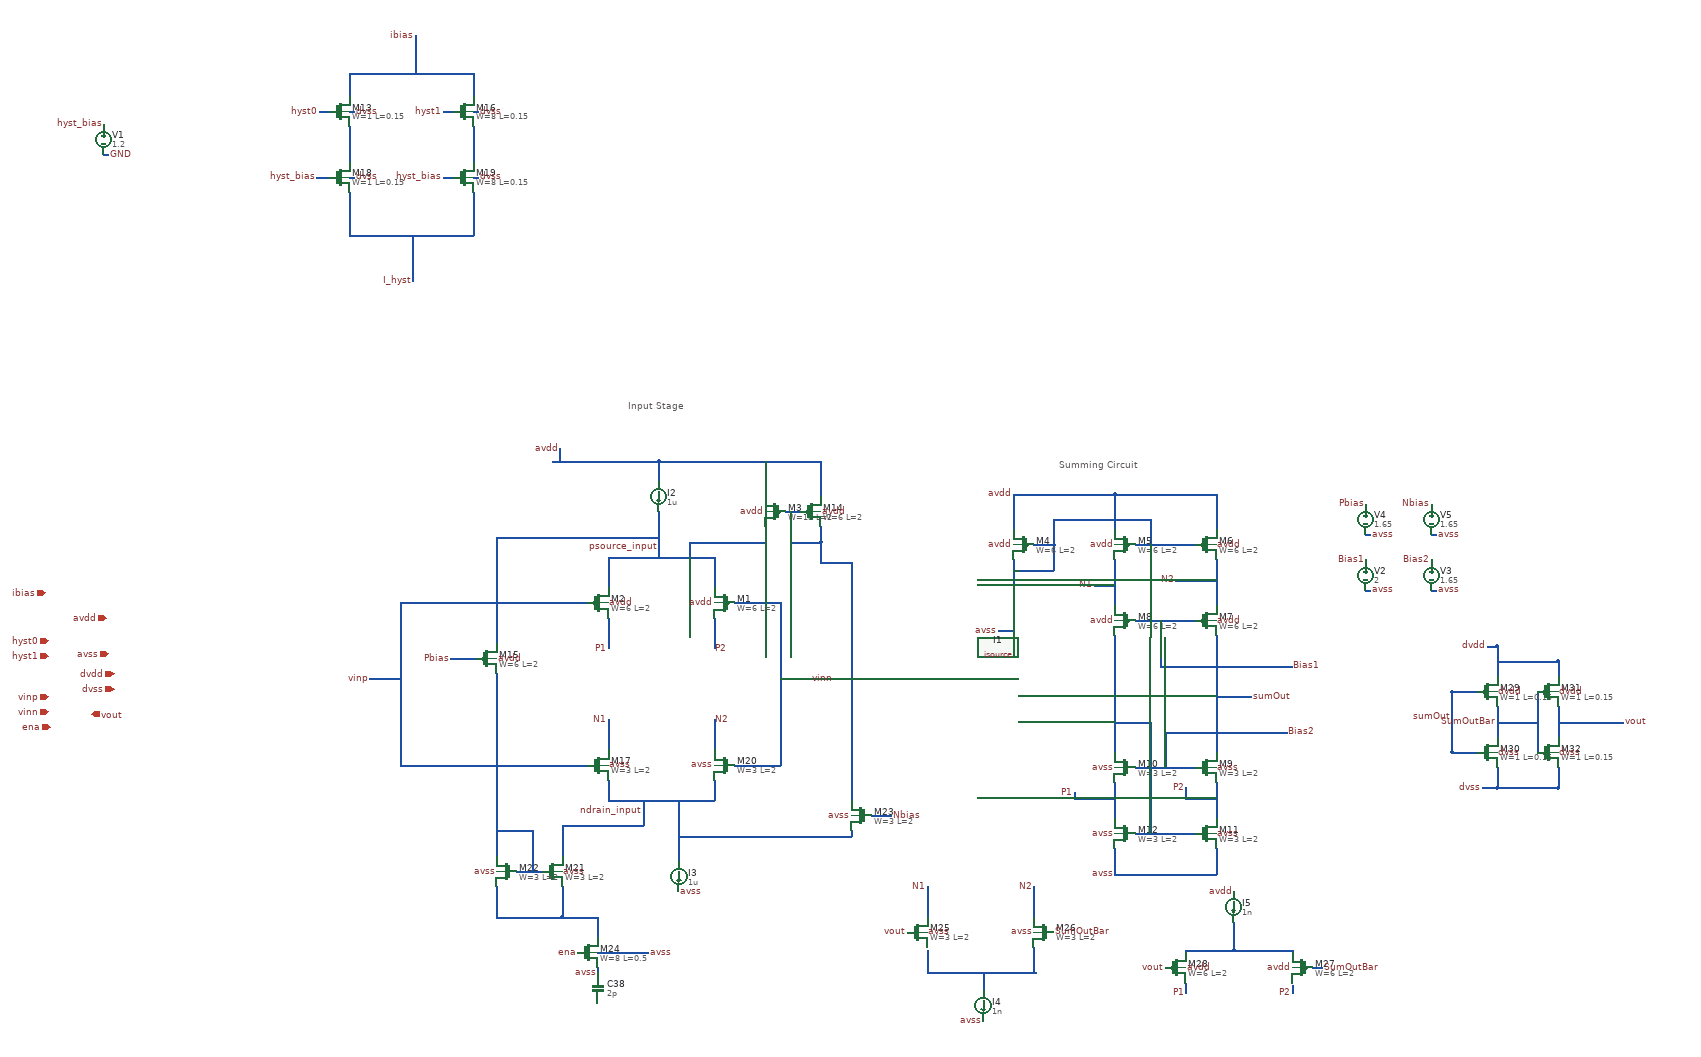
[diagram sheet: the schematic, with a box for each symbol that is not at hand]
v {xschem version=3.4.5 file_version=1.2
}
G {}
K {}
V {}
S {}
E {}
T {Summing Circuit} 2105 -1180 0 0 0.5 0.5 {}
T {Input Stage} 1255 -1295 0 0 0.5 0.5 {}
N 705 -1865 715 -1865 {
lab=dvss}
N 830 -1550 830 -1530 {
lab=I_hyst}
N 830 -1570 830 -1550 {
lab=I_hyst}
N 830 -1620 830 -1570 {
lab=I_hyst}
N 950 -1865 960 -1865 {
lab=dvss}
N 890 -1865 910 -1865 {
lab=hyst1}
N 950 -1835 950 -1765 {
lab=#net1}
N 950 -1735 960 -1735 {
lab=dvss}
N 705 -1835 705 -1765 {
lab=#net2}
N 705 -1835 705 -1765 {
lab=#net2}
N 950 -1705 950 -1675 {
lab=I_hyst}
N 705 -1685 705 -1620 {
lab=I_hyst}
N 705 -1705 705 -1685 {
lab=I_hyst}
N 950 -1675 950 -1620 {
lab=I_hyst}
N 705 -1735 715 -1735 {
lab=dvss}
N 950 -1940 950 -1895 {
lab=ibias}
N 705 -1940 705 -1895 {
lab=ibias}
N 705 -1620 950 -1620 {
lab=I_hyst}
N 705 -1940 950 -1940 {
lab=ibias}
N 835 -2015 835 -1940 {
lab=ibias}
N 890 -1735 910 -1735 {
lab=hyst_bias}
N 640 -1735 665 -1735 {
lab=hyst_bias}
N 645 -1865 665 -1865 {
lab=hyst0}
N 220 -1780 230 -1780 {
lab=GND}
N 2970 -690 2970 -630 {
lab=SumOutBar}
N 2880 -720 2930 -720 {
lab=sumOut}
N 2880 -600 2930 -600 {
lab=sumOut}
N 2880 -720 2880 -600 {
lab=sumOut}
N 3090 -660 3220 -660 {
lab=vout}
N 2970 -810 2970 -750 {
lab=dvdd}
N 2950 -810 2970 -810 {
lab=dvdd}
N 2970 -570 2970 -530 {
lab=dvss}
N 2940 -530 2970 -530 {
lab=dvss}
N 2710 -920 2720 -920 {
lab=avss}
N 2840 -920 2850 -920 {
lab=avss}
N 2710 -1030 2720 -1030 {
lab=avss}
N 2840 -1030 2850 -1030 {
lab=avss}
N 3090 -690 3090 -630 {
lab=vout}
N 3050 -720 3050 -600 {
lab=SumOutBar}
N 3090 -780 3090 -750 {
lab=dvdd}
N 2970 -780 3090 -780 {
lab=dvdd}
N 3090 -570 3090 -530 {
lab=dvss}
N 2970 -530 3090 -530 {
lab=dvss}
N 2970 -690 2970 -630 {
lab=SumOutBar}
N 2880 -720 2930 -720 {
lab=sumOut}
N 2880 -600 2930 -600 {
lab=sumOut}
N 2880 -720 2880 -600 {
lab=sumOut}
N 3090 -660 3220 -660 {
lab=vout}
N 2970 -810 2970 -750 {
lab=dvdd}
N 2950 -810 2970 -810 {
lab=dvdd}
N 2970 -570 2970 -530 {
lab=dvss}
N 2940 -530 2970 -530 {
lab=dvss}
N 3090 -690 3090 -630 {
lab=vout}
N 3050 -720 3050 -600 {
lab=SumOutBar}
N 3090 -780 3090 -750 {
lab=dvdd}
N 2970 -780 3090 -780 {
lab=dvdd}
N 3090 -570 3090 -530 {
lab=dvss}
N 2970 -530 3090 -530 {
lab=dvss}
N 2970 -660 3050 -660 {
lab=SumOutBar}
N 2015 -980 2015 -930 {
lab=#net3}
N 2015 -960 2095 -960 {
lab=#net3}
N 2095 -1010 2095 -960 {
lab=#net3}
N 2055 -1010 2095 -1010 {
lab=#net3}
N 2015 -1110 2015 -1040 {
lab=avdd}
N 2015 -1110 2215 -1110 {
lab=avdd}
N 2215 -1110 2215 -1040 {
lab=avdd}
N 2215 -1110 2395 -1110 {
lab=avdd}
N 2415 -1110 2415 -1040 {
lab=avdd}
N 2395 -1110 2415 -1110 {
lab=avdd}
N 2255 -1010 2375 -1010 {
lab=#net3}
N 2285 -1060 2285 -1010 {
lab=#net3}
N 2095 -1060 2285 -1060 {
lab=#net3}
N 2095 -1060 2095 -1010 {
lab=#net3}
N 2215 -980 2215 -920 {
lab=N1}
N 2415 -980 2415 -890 {
lab=N2}
N 2335 -940 2415 -940 {
lab=N2}
N 2335 -860 2375 -860 {
lab=Bias1}
N 2255 -860 2335 -860 {
lab=Bias1}
N 2215 -920 2215 -890 {
lab=N1}
N 2415 -830 2415 -600 {
lab=sumOut}
N 2215 -830 2215 -600 {
lab=#net4}
N 2255 -570 2375 -570 {
lab=Bias2}
N 2415 -540 2415 -470 {
lab=P2}
N 2355 -510 2415 -510 {
lab=P2}
N 2355 -530 2355 -510 {
lab=P2}
N 2215 -540 2215 -470 {
lab=P1}
N 2255 -440 2375 -440 {
lab=#net4}
N 2215 -410 2215 -360 {
lab=avss}
N 2215 -360 2415 -360 {
lab=avss}
N 2415 -410 2415 -360 {
lab=avss}
N 2135 -510 2215 -510 {
lab=P1}
N 2135 -520 2135 -510 {
lab=P1}
N 2285 -660 2285 -440 {
lab=#net4}
N 2215 -660 2285 -660 {
lab=#net4}
N 2175 -930 2215 -930 {
lab=N1}
N 2305 -860 2305 -770 {
lab=Bias1}
N 2305 -770 2565 -770 {
lab=Bias1}
N 2315 -640 2315 -570 {
lab=Bias2}
N 2315 -640 2555 -640 {
lab=Bias2}
N 2015 -870 2015 -840 {
lab=avss}
N 1985 -840 2015 -840 {
lab=avss}
N 2415 -710 2485 -710 {
lab=sumOut}
N 1195 -205 1295 -205 {lab=avss}
N 1195 -175 1195 -145 {lab=avss}
N 1425 -985 1425 -925 {
lab=psource_input}
N 1215 -985 1425 -985 {
lab=psource_input}
N 1215 -985 1215 -925 {
lab=psource_input}
N 1315 -1015 1315 -985 {
lab=psource_input}
N 1265 -1175 1315 -1175 {
lab=avdd}
N 1565 -1075 1595 -1075 {
lab=#net5}
N 1315 -1175 1585 -1175 {
lab=avdd}
N 1635 -1175 1635 -1105 {
lab=avdd}
N 1525 -1175 1525 -1105 {
lab=avdd}
N 1575 -1075 1575 -1015 {
lab=#net5}
N 1575 -1015 1635 -1015 {
lab=#net5}
N 1635 -1045 1635 -1015 {
lab=#net5}
N 1525 -1045 1525 -1015 {
lab=psource_input}
N 1375 -1015 1475 -1015 {
lab=psource_input}
N 1375 -1015 1375 -985 {
lab=psource_input}
N 1425 -865 1425 -805 {
lab=P2}
N 1215 -865 1215 -805 {
lab=P1}
N 1105 -1025 1315 -1025 {
lab=psource_input}
N 995 -975 995 -925 {
lab=psource_input}
N 995 -1025 995 -975 {
lab=psource_input}
N 1045 -1025 1105 -1025 {
lab=psource_input}
N 905 -785 955 -785 {
lab=Pbias}
N 995 -925 995 -815 {
lab=psource_input}
N 805 -895 1175 -895 {
lab=vinp}
N 1425 -655 1425 -605 {
lab=N2}
N 1215 -665 1215 -605 {
lab=N1}
N 1425 -665 1425 -655 {
lab=N2}
N 1035 -365 1085 -365 {
lab=#net6}
N 1215 -545 1215 -505 {
lab=ndrain_input}
N 1215 -505 1425 -505 {
lab=ndrain_input}
N 1425 -545 1425 -505 {
lab=ndrain_input}
N 1285 -505 1285 -455 {
lab=ndrain_input}
N 1125 -455 1285 -455 {
lab=ndrain_input}
N 1125 -455 1125 -395 {
lab=ndrain_input}
N 995 -1025 1045 -1025 {
lab=psource_input}
N 995 -755 995 -395 {
lab=#net6}
N 805 -575 1175 -575 {
lab=vinp}
N 995 -335 995 -275 {
lab=#net7}
N 995 -275 1125 -275 {
lab=#net7}
N 1125 -335 1125 -275 {
lab=#net7}
N 1465 -575 1555 -575 {
lab=vinn}
N 1355 -505 1355 -385 {
lab=ndrain_input}
N 1475 -1015 1525 -1015 {
lab=psource_input}
N 1585 -1175 1635 -1175 {
lab=avdd}
N 1465 -895 1485 -895 {
lab=vinn}
N 1485 -895 1505 -895 {
lab=vinn}
N 1555 -895 1555 -575 {
lab=vinn}
N 1505 -895 1555 -895 {
lab=vinn}
N 1555 -745 1585 -745 {
lab=vinn}
N 1585 -745 1615 -745 {
lab=vinn}
N 1065 -445 1065 -365 {
lab=#net6}
N 995 -445 1065 -445 {
lab=#net6}
N 1355 -435 1635 -435 {
lab=ndrain_input}
N 1635 -435 1695 -435 {
lab=ndrain_input}
N 1695 -445 1695 -435 {
lab=ndrain_input}
N 1695 -975 1695 -505 {
lab=#net5}
N 1635 -975 1695 -975 {
lab=#net5}
N 1635 -1015 1635 -975 {
lab=#net5}
N 1735 -475 1775 -475 {
lab=Nbias}
N 1195 -275 1195 -235 {
lab=#net7}
N 1105 -1175 1265 -1175 {
lab=avdd}
N 1120 -1200 1120 -1175 {
lab=avdd}
N 1315 -1025 1315 -1015 {
lab=psource_input}
N 1125 -275 1195 -275 {
lab=#net7}
N 805 -895 805 -575 {
lab=vinp}
N 745 -745 775 -745 {
lab=vinp}
N 775 -745 805 -745 {
lab=vinp}
N 1315 -1075 1315 -1020 {
lab=psource_input}
N 1315 -1175 1315 -1135 {
lab=avdd}
N 2055 -325 2055 -275 {
lab=N2}
N 1845 -335 1845 -275 {
lab=N1}
N 2055 -335 2055 -325 {
lab=N2}
N 1845 -210 1845 -170 {
lab=#net8}
N 1845 -165 2060 -165 {
lab=#net8}
N 2055 -215 2055 -165 {
lab=#net8}
N 1845 -170 1845 -165 {
lab=#net8}
N 1955 -165 1955 -130 {
lab=#net8}
N 2605 -175 2625 -175 {
lab=SumOutBar}
N 2450 -265 2450 -210 {
lab=#net9}
N 2450 -210 2565 -210 {
lab=#net9}
N 2565 -210 2565 -205 {
lab=#net9}
N 2355 -210 2450 -210 {
lab=#net9}
N 2355 -210 2355 -205 {
lab=#net9}
N 2355 -145 2355 -125 {
lab=P1}
N 2565 -140 2565 -125 {
lab=P2}
C {devices/ipin.sym} 110 -710 0 0 {name=p48 lab=vinp
}
C {devices/ipin.sym} 110 -680 0 0 {name=p4 lab=vinn
}
C {devices/ipin.sym} 110 -820 0 0 {name=p19 lab=hyst0
}
C {devices/ipin.sym} 110 -790 0 0 {name=p20 lab=hyst1
}
C {devices/lab_pin.sym} 830 -1530 0 0 {name=p31 sig_type=std_logic lab=I_hyst

}
C {sky130_fd_pr/nfet_01v8.sym} 685 -1865 0 0 {name=M13
L=0.15
W=1
mult=2 nf=1
model=nfet_01v8
spiceprefix=X}
C {devices/ipin.sym} 225 -865 0 0 {name=p37 lab=avdd
}
C {devices/ipin.sym} 230 -795 0 0 {name=p38 lab=avss
}
C {devices/ipin.sym} 240 -755 0 0 {name=p39 lab=dvdd
}
C {devices/ipin.sym} 240 -725 0 0 {name=p40 lab=dvss
}
C {devices/opin.sym} 195 -675 0 0 { name=p116 lab=vout}
C {devices/ipin.sym} 115 -650 0 0 {name=p42 lab=ena
}
C {devices/lab_pin.sym} 890 -1865 0 0 {name=p18 sig_type=std_logic lab=hyst1

}
C {sky130_fd_pr/nfet_01v8.sym} 930 -1865 0 0 {name=M16
L=0.15
W=8
mult=2 nf=1
model=nfet_01v8
spiceprefix=X}
C {sky130_fd_pr/nfet_01v8.sym} 930 -1735 0 0 {name=M19
L=0.15
W=8
mult=2 nf=1
model=nfet_01v8
spiceprefix=X}
C {devices/ipin.sym} 105 -915 0 0 {name=p27 lab=ibias
}
C {sky130_fd_pr/nfet_01v8.sym} 685 -1735 0 0 {name=M18
L=0.15
W=1
mult=2 nf=1
model=nfet_01v8
spiceprefix=X}
C {devices/lab_pin.sym} 715 -1735 0 1 {name=p33 sig_type=std_logic lab=dvss

}
C {devices/lab_pin.sym} 835 -2015 0 0 {name=p21 sig_type=std_logic lab=ibias


}
C {devices/lab_pin.sym} 645 -1865 0 0 {name=p25 sig_type=std_logic lab=hyst0

}
C {devices/vsource.sym} 220 -1810 0 0 {name=V1 value=1.2 savecurrent=false}
C {devices/lab_pin.sym} 230 -1780 0 1 {name=p22 sig_type=std_logic lab=GND

}
C {devices/lab_pin.sym} 640 -1735 0 0 {name=p26 sig_type=std_logic lab=hyst_bias


}
C {devices/lab_pin.sym} 890 -1735 0 0 {name=p28 sig_type=std_logic lab=hyst_bias


}
C {devices/lab_pin.sym} 220 -1840 0 0 {name=p29 sig_type=std_logic lab=hyst_bias


}
C {devices/lab_pin.sym} 715 -1865 0 1 {name=p23 sig_type=std_logic lab=dvss

}
C {devices/lab_pin.sym} 960 -1865 0 1 {name=p24 sig_type=std_logic lab=dvss

}
C {devices/lab_pin.sym} 960 -1735 0 1 {name=p30 sig_type=std_logic lab=dvss

}
C {devices/vsource.sym} 2710 -950 0 0 {name=V2 value=2 savecurrent=false}
C {devices/lab_pin.sym} 2710 -980 0 0 {name=p15 sig_type=std_logic lab=Bias1


}
C {devices/vsource.sym} 2840 -950 0 0 {name=V3 value=1.65 savecurrent=false}
C {devices/lab_pin.sym} 2840 -980 0 0 {name=p17 sig_type=std_logic lab=Bias2


}
C {devices/vsource.sym} 2710 -1060 0 0 {name=V4 value=1.65 savecurrent=false}
C {devices/lab_pin.sym} 2710 -1090 0 0 {name=p34 sig_type=std_logic lab=Pbias


}
C {devices/vsource.sym} 2840 -1060 0 0 {name=V5 value=1.65 savecurrent=false}
C {devices/lab_pin.sym} 2840 -1090 0 0 {name=p36 sig_type=std_logic lab=Nbias


}
C {devices/lab_pin.sym} 2850 -920 0 1 {name=p14 lab=avss
}
C {devices/lab_pin.sym} 2720 -920 0 1 {name=p16 lab=avss
}
C {devices/lab_pin.sym} 2720 -1030 0 1 {name=p32 lab=avss
}
C {devices/lab_pin.sym} 2850 -1030 0 1 {name=p35 lab=avss
}
C {sky130_fd_pr/pfet_01v8.sym} 2950 -720 0 0 {name=M29
L=0.15
W=1
nf=1
mult=1
ad="'int((nf+1)/2) * W/nf * 0.29'" 
pd="'2*int((nf+1)/2) * (W/nf + 0.29)'"
as="'int((nf+2)/2) * W/nf * 0.29'" 
ps="'2*int((nf+2)/2) * (W/nf + 0.29)'"
nrd="'0.29 / W'" nrs="'0.29 / W'"
sa=0 sb=0 sd=0
model=pfet_01v8
spiceprefix=X
}
C {devices/lab_pin.sym} 2880 -670 0 0 {name=l38 lab=sumOut
}
C {devices/lab_pin.sym} 3220 -660 0 1 {name=l39 lab=vout
}
C {devices/lab_pin.sym} 2950 -810 0 0 {name=l40 lab=dvdd
}
C {devices/lab_pin.sym} 2940 -530 0 0 {name=l41 lab=dvss
}
C {sky130_fd_pr/nfet_01v8.sym} 2950 -600 0 0 {name=M30
L=0.15
W=1
nf=1 
mult=1
ad="'int((nf+1)/2) * W/nf * 0.29'" 
pd="'2*int((nf+1)/2) * (W/nf + 0.29)'"
as="'int((nf+2)/2) * W/nf * 0.29'" 
ps="'2*int((nf+2)/2) * (W/nf + 0.29)'"
nrd="'0.29 / W'" nrs="'0.29 / W'"
sa=0 sb=0 sd=0
model=nfet_01v8
spiceprefix=X
}
C {sky130_fd_pr/pfet_01v8.sym} 3070 -720 0 0 {name=M31
L=0.15
W=1
nf=1
mult=1
ad="'int((nf+1)/2) * W/nf * 0.29'" 
pd="'2*int((nf+1)/2) * (W/nf + 0.29)'"
as="'int((nf+2)/2) * W/nf * 0.29'" 
ps="'2*int((nf+2)/2) * (W/nf + 0.29)'"
nrd="'0.29 / W'" nrs="'0.29 / W'"
sa=0 sb=0 sd=0
model=pfet_01v8
spiceprefix=X
}
C {sky130_fd_pr/nfet_01v8.sym} 3070 -600 0 0 {name=M32
L=0.15
W=1
nf=1 
mult=1
ad="'int((nf+1)/2) * W/nf * 0.29'" 
pd="'2*int((nf+1)/2) * (W/nf + 0.29)'"
as="'int((nf+2)/2) * W/nf * 0.29'" 
ps="'2*int((nf+2)/2) * (W/nf + 0.29)'"
nrd="'0.29 / W'" nrs="'0.29 / W'"
sa=0 sb=0 sd=0
model=nfet_01v8
spiceprefix=X
}
C {devices/lab_pin.sym} 3090 -600 0 1 {name=l42 lab=dvss
}
C {devices/lab_pin.sym} 2970 -600 0 1 {name=l43 lab=dvss
}
C {devices/lab_pin.sym} 2970 -720 0 1 {name=l44 lab=dvdd
}
C {devices/lab_pin.sym} 3090 -720 0 1 {name=l45 lab=dvdd
}
C {sky130_fd_pr/pfet_g5v0d10v5.sym} 2035 -1010 0 1 {name=M4
L=2
W=6
nf=1
mult=1
ad="'int((nf+1)/2) * W/nf * 0.29'" 
pd="'2*int((nf+1)/2) * (W/nf + 0.29)'"
as="'int((nf+2)/2) * W/nf * 0.29'" 
ps="'2*int((nf+2)/2) * (W/nf + 0.29)'"
nrd="'0.29 / W'" nrs="'0.29 / W'"
sa=0 sb=0 sd=0
model=pfet_g5v0d10v5
spiceprefix=X
}
C {sky130_fd_pr/pfet_g5v0d10v5.sym} 2235 -1010 0 1 {name=M5
L=2
W=6
nf=1
mult=1
ad="'int((nf+1)/2) * W/nf * 0.29'" 
pd="'2*int((nf+1)/2) * (W/nf + 0.29)'"
as="'int((nf+2)/2) * W/nf * 0.29'" 
ps="'2*int((nf+2)/2) * (W/nf + 0.29)'"
nrd="'0.29 / W'" nrs="'0.29 / W'"
sa=0 sb=0 sd=0
model=pfet_g5v0d10v5
spiceprefix=X
}
C {sky130_fd_pr/pfet_g5v0d10v5.sym} 2395 -1010 0 0 {name=M6
L=2
W=6
nf=1
mult=1
ad="'int((nf+1)/2) * W/nf * 0.29'" 
pd="'2*int((nf+1)/2) * (W/nf + 0.29)'"
as="'int((nf+2)/2) * W/nf * 0.29'" 
ps="'2*int((nf+2)/2) * (W/nf + 0.29)'"
nrd="'0.29 / W'" nrs="'0.29 / W'"
sa=0 sb=0 sd=0
model=pfet_g5v0d10v5
spiceprefix=X
}
C {sky130_fd_pr/pfet_g5v0d10v5.sym} 2395 -860 0 0 {name=M7
L=2
W=6
nf=1
mult=1
ad="'int((nf+1)/2) * W/nf * 0.29'" 
pd="'2*int((nf+1)/2) * (W/nf + 0.29)'"
as="'int((nf+2)/2) * W/nf * 0.29'" 
ps="'2*int((nf+2)/2) * (W/nf + 0.29)'"
nrd="'0.29 / W'" nrs="'0.29 / W'"
sa=0 sb=0 sd=0
model=pfet_g5v0d10v5
spiceprefix=X
}
C {sky130_fd_pr/pfet_g5v0d10v5.sym} 2235 -860 0 1 {name=M8
L=2
W=6
nf=1
mult=1
ad="'int((nf+1)/2) * W/nf * 0.29'" 
pd="'2*int((nf+1)/2) * (W/nf + 0.29)'"
as="'int((nf+2)/2) * W/nf * 0.29'" 
ps="'2*int((nf+2)/2) * (W/nf + 0.29)'"
nrd="'0.29 / W'" nrs="'0.29 / W'"
sa=0 sb=0 sd=0
model=pfet_g5v0d10v5
spiceprefix=X
}
C {sky130_fd_pr/nfet_g5v0d10v5.sym} 2395 -570 0 0 {name=M9
L=2
W=3
nf=1
mult=1
ad="'int((nf+1)/2) * W/nf * 0.29'" 
pd="'2*int((nf+1)/2) * (W/nf + 0.29)'"
as="'int((nf+2)/2) * W/nf * 0.29'" 
ps="'2*int((nf+2)/2) * (W/nf + 0.29)'"
nrd="'0.29 / W'" nrs="'0.29 / W'"
sa=0 sb=0 sd=0
model=nfet_g5v0d10v5
spiceprefix=X
}
C {devices/lab_pin.sym} 2335 -940 0 0 {name=l1 lab=N2}
C {sky130_fd_pr/nfet_g5v0d10v5.sym} 2235 -570 0 1 {name=M10
L=2
W=3
nf=1
mult=1
ad="'int((nf+1)/2) * W/nf * 0.29'" 
pd="'2*int((nf+1)/2) * (W/nf + 0.29)'"
as="'int((nf+2)/2) * W/nf * 0.29'" 
ps="'2*int((nf+2)/2) * (W/nf + 0.29)'"
nrd="'0.29 / W'" nrs="'0.29 / W'"
sa=0 sb=0 sd=0
model=nfet_g5v0d10v5
spiceprefix=X
}
C {sky130_fd_pr/nfet_g5v0d10v5.sym} 2395 -440 0 0 {name=M11
L=2
W=3
nf=1
mult=1
ad="'int((nf+1)/2) * W/nf * 0.29'" 
pd="'2*int((nf+1)/2) * (W/nf + 0.29)'"
as="'int((nf+2)/2) * W/nf * 0.29'" 
ps="'2*int((nf+2)/2) * (W/nf + 0.29)'"
nrd="'0.29 / W'" nrs="'0.29 / W'"
sa=0 sb=0 sd=0
model=nfet_g5v0d10v5
spiceprefix=X
}
C {devices/lab_pin.sym} 2355 -530 0 0 {name=l2 lab=P2
}
C {sky130_fd_pr/nfet_g5v0d10v5.sym} 2235 -440 0 1 {name=M12
L=2
W=3
nf=1
mult=1
ad="'int((nf+1)/2) * W/nf * 0.29'" 
pd="'2*int((nf+1)/2) * (W/nf + 0.29)'"
as="'int((nf+2)/2) * W/nf * 0.29'" 
ps="'2*int((nf+2)/2) * (W/nf + 0.29)'"
nrd="'0.29 / W'" nrs="'0.29 / W'"
sa=0 sb=0 sd=0
model=nfet_g5v0d10v5
spiceprefix=X
}
C {devices/lab_pin.sym} 2135 -520 0 0 {name=l3 lab=P1
}
C {devices/lab_pin.sym} 2175 -930 0 0 {name=l4 lab=N1}
C {devices/lab_pin.sym} 2565 -770 0 1 {name=l5 lab=Bias1
}
C {devices/lab_pin.sym} 2555 -640 0 1 {name=l6 lab=Bias2
}
C {devices/isource.sym} 2015 -905 0 0 {name=I1 value=1u}
C {devices/lab_pin.sym} 1985 -840 0 0 {name=p1 lab=avss
}
C {devices/lab_pin.sym} 2015 -1010 0 0 {name=l24 lab=avdd
}
C {devices/lab_pin.sym} 2215 -1010 0 0 {name=l25 lab=avdd
}
C {devices/lab_pin.sym} 2415 -1010 0 1 {name=l26 lab=avdd
}
C {devices/lab_pin.sym} 2415 -860 0 1 {name=l27 lab=avdd
}
C {devices/lab_pin.sym} 2215 -860 0 0 {name=l28 lab=avdd
}
C {devices/lab_pin.sym} 2015 -1110 0 0 {name=l29 lab=avdd
}
C {devices/lab_pin.sym} 2215 -570 0 0 {name=p8 lab=avss
}
C {devices/lab_pin.sym} 2415 -570 0 1 {name=p9 lab=avss
}
C {devices/lab_pin.sym} 2415 -440 0 1 {name=p10 lab=avss
}
C {devices/lab_pin.sym} 2215 -440 0 0 {name=p11 lab=avss
}
C {devices/lab_pin.sym} 2215 -360 0 0 {name=p12 lab=avss
}
C {devices/lab_pin.sym} 2485 -710 0 1 {name=l15 lab=sumOut
}
C {devices/lab_pin.sym} 1155 -205 0 0 {name=l56 lab=ena}
C {devices/lab_pin.sym} 1195 -165 0 0 {name=p284 lab=avss
}
C {devices/parax_cap.sym} 1195 -135 0 0 {name=C38  value=2p}
C {devices/lab_pin.sym} 1295 -205 0 1 {name=p43 sig_type=std_logic lab=avss


}
C {sky130_fd_pr/nfet_g5v0d10v5.sym} 1175 -205 0 0 {name=M24
L=0.5
W=8
nf=1
mult=2
ad="'int((nf+1)/2) * W/nf * 0.29'" 
pd="'2*int((nf+1)/2) * (W/nf + 0.29)'"
as="'int((nf+2)/2) * W/nf * 0.29'" 
ps="'2*int((nf+2)/2) * (W/nf + 0.29)'"
nrd="'0.29 / W'" nrs="'0.29 / W'"
sa=0 sb=0 sd=0
model=nfet_g5v0d10v5
spiceprefix=X
}
C {sky130_fd_pr/pfet_g5v0d10v5.sym} 1445 -895 0 1 {name=M1
L=2
W=6
nf=1
mult=1
ad="'int((nf+1)/2) * W/nf * 0.29'" 
pd="'2*int((nf+1)/2) * (W/nf + 0.29)'"
as="'int((nf+2)/2) * W/nf * 0.29'" 
ps="'2*int((nf+2)/2) * (W/nf + 0.29)'"
nrd="'0.29 / W'" nrs="'0.29 / W'"
sa=0 sb=0 sd=0
model=pfet_g5v0d10v5
spiceprefix=X
}
C {sky130_fd_pr/pfet_g5v0d10v5.sym} 1195 -895 0 0 {name=M2
L=2
W=6
nf=1
mult=1
ad="'int((nf+1)/2) * W/nf * 0.29'" 
pd="'2*int((nf+1)/2) * (W/nf + 0.29)'"
as="'int((nf+2)/2) * W/nf * 0.29'" 
ps="'2*int((nf+2)/2) * (W/nf + 0.29)'"
nrd="'0.29 / W'" nrs="'0.29 / W'"
sa=0 sb=0 sd=0
model=pfet_g5v0d10v5
spiceprefix=X
}
C {sky130_fd_pr/pfet_g5v0d10v5.sym} 1545 -1075 0 1 {name=M3
L=2
W=18
nf=1
mult=1
ad="'int((nf+1)/2) * W/nf * 0.29'" 
pd="'2*int((nf+1)/2) * (W/nf + 0.29)'"
as="'int((nf+2)/2) * W/nf * 0.29'" 
ps="'2*int((nf+2)/2) * (W/nf + 0.29)'"
nrd="'0.29 / W'" nrs="'0.29 / W'"
sa=0 sb=0 sd=0
model=pfet_g5v0d10v5
spiceprefix=X
}
C {sky130_fd_pr/pfet_g5v0d10v5.sym} 1615 -1075 0 0 {name=M14
L=2
W=6
nf=1
mult=1
ad="'int((nf+1)/2) * W/nf * 0.29'" 
pd="'2*int((nf+1)/2) * (W/nf + 0.29)'"
as="'int((nf+2)/2) * W/nf * 0.29'" 
ps="'2*int((nf+2)/2) * (W/nf + 0.29)'"
nrd="'0.29 / W'" nrs="'0.29 / W'"
sa=0 sb=0 sd=0
model=pfet_g5v0d10v5
spiceprefix=X
}
C {devices/lab_pin.sym} 1425 -805 0 1 {name=l7 lab=P2}
C {devices/lab_pin.sym} 1215 -805 0 0 {name=l8 lab=P1}
C {sky130_fd_pr/pfet_g5v0d10v5.sym} 975 -785 0 0 {name=M15
L=2
W=6
nf=1
mult=1
ad="'int((nf+1)/2) * W/nf * 0.29'" 
pd="'2*int((nf+1)/2) * (W/nf + 0.29)'"
as="'int((nf+2)/2) * W/nf * 0.29'" 
ps="'2*int((nf+2)/2) * (W/nf + 0.29)'"
nrd="'0.29 / W'" nrs="'0.29 / W'"
sa=0 sb=0 sd=0
model=pfet_g5v0d10v5
spiceprefix=X
}
C {sky130_fd_pr/nfet_g5v0d10v5.sym} 1195 -575 0 0 {name=M17
L=2
W=3
nf=1
mult=1
ad="'int((nf+1)/2) * W/nf * 0.29'" 
pd="'2*int((nf+1)/2) * (W/nf + 0.29)'"
as="'int((nf+2)/2) * W/nf * 0.29'" 
ps="'2*int((nf+2)/2) * (W/nf + 0.29)'"
nrd="'0.29 / W'" nrs="'0.29 / W'"
sa=0 sb=0 sd=0
model=nfet_g5v0d10v5
spiceprefix=X
}
C {sky130_fd_pr/nfet_g5v0d10v5.sym} 1445 -575 0 1 {name=M20
L=2
W=3
nf=1
mult=1
ad="'int((nf+1)/2) * W/nf * 0.29'" 
pd="'2*int((nf+1)/2) * (W/nf + 0.29)'"
as="'int((nf+2)/2) * W/nf * 0.29'" 
ps="'2*int((nf+2)/2) * (W/nf + 0.29)'"
nrd="'0.29 / W'" nrs="'0.29 / W'"
sa=0 sb=0 sd=0
model=nfet_g5v0d10v5
spiceprefix=X
}
C {devices/lab_pin.sym} 1425 -665 0 1 {name=l10 lab=N2}
C {devices/lab_pin.sym} 1215 -665 0 0 {name=l11 lab=N1}
C {sky130_fd_pr/nfet_g5v0d10v5.sym} 1105 -365 0 0 {name=M21
L=2
W=3
nf=1
mult=1
ad="'int((nf+1)/2) * W/nf * 0.29'" 
pd="'2*int((nf+1)/2) * (W/nf + 0.29)'"
as="'int((nf+2)/2) * W/nf * 0.29'" 
ps="'2*int((nf+2)/2) * (W/nf + 0.29)'"
nrd="'0.29 / W'" nrs="'0.29 / W'"
sa=0 sb=0 sd=0
model=nfet_g5v0d10v5
spiceprefix=X
}
C {sky130_fd_pr/nfet_g5v0d10v5.sym} 1015 -365 0 1 {name=M22
L=2
W=3
nf=1
mult=1
ad="'int((nf+1)/2) * W/nf * 0.29'" 
pd="'2*int((nf+1)/2) * (W/nf + 0.29)'"
as="'int((nf+2)/2) * W/nf * 0.29'" 
ps="'2*int((nf+2)/2) * (W/nf + 0.29)'"
nrd="'0.29 / W'" nrs="'0.29 / W'"
sa=0 sb=0 sd=0
model=nfet_g5v0d10v5
spiceprefix=X
}
C {devices/lab_pin.sym} 1615 -745 0 1 {name=l13 lab=vinn
}
C {devices/lab_pin.sym} 1120 -1200 0 0 {name=l14 lab=avdd
}
C {sky130_fd_pr/nfet_g5v0d10v5.sym} 1715 -475 0 1 {name=M23
L=2
W=3
nf=1
mult=1
ad="'int((nf+1)/2) * W/nf * 0.29'" 
pd="'2*int((nf+1)/2) * (W/nf + 0.29)'"
as="'int((nf+2)/2) * W/nf * 0.29'" 
ps="'2*int((nf+2)/2) * (W/nf + 0.29)'"
nrd="'0.29 / W'" nrs="'0.29 / W'"
sa=0 sb=0 sd=0
model=nfet_g5v0d10v5
spiceprefix=X
}
C {devices/lab_pin.sym} 1775 -475 0 1 {name=l16 lab=Nbias
}
C {devices/lab_pin.sym} 1425 -895 0 0 {name=l18 lab=avdd
}
C {devices/lab_pin.sym} 1215 -895 0 1 {name=l19 lab=avdd
}
C {devices/lab_pin.sym} 995 -785 0 1 {name=l21 lab=avdd
}
C {devices/lab_pin.sym} 1125 -365 0 1 {name=p2 sig_type=std_logic lab=avss


}
C {devices/lab_pin.sym} 995 -365 0 0 {name=p3 sig_type=std_logic lab=avss


}
C {devices/lab_pin.sym} 1425 -575 0 0 {name=p5 sig_type=std_logic lab=avss


}
C {devices/lab_pin.sym} 1215 -575 0 1 {name=p6 sig_type=std_logic lab=avss


}
C {devices/lab_pin.sym} 1695 -475 0 0 {name=p7 sig_type=std_logic lab=avss


}
C {devices/lab_pin.sym} 1525 -1075 0 0 {name=l22 lab=avdd
}
C {devices/lab_pin.sym} 1635 -1075 0 1 {name=l23 lab=avdd
}
C {devices/lab_pin.sym} 1315 -1005 0 0 {name=l34 lab=psource_input
}
C {devices/lab_pin.sym} 1285 -485 0 0 {name=l35 lab=ndrain_input
}
C {devices/lab_pin.sym} 745 -745 0 0 {name=l12 lab=vinp
}
C {devices/lab_pin.sym} 905 -785 0 0 {name=l17 lab=Pbias
}
C {devices/isource.sym} 1315 -1105 0 0 {name=I2 value=1u}
C {devices/isource.sym} 1355 -355 0 0 {name=I3 value=1u}
C {devices/lab_pin.sym} 1355 -325 0 1 {name=p13 sig_type=std_logic lab=avss


}
C {sky130_fd_pr/nfet_g5v0d10v5.sym} 1825 -245 0 0 {name=M25
L=2
W=3
nf=1
mult=1
ad="'int((nf+1)/2) * W/nf * 0.29'" 
pd="'2*int((nf+1)/2) * (W/nf + 0.29)'"
as="'int((nf+2)/2) * W/nf * 0.29'" 
ps="'2*int((nf+2)/2) * (W/nf + 0.29)'"
nrd="'0.29 / W'" nrs="'0.29 / W'"
sa=0 sb=0 sd=0
model=nfet_g5v0d10v5
spiceprefix=X
}
C {sky130_fd_pr/nfet_g5v0d10v5.sym} 2075 -245 0 1 {name=M26
L=2
W=3
nf=1
mult=1
ad="'int((nf+1)/2) * W/nf * 0.29'" 
pd="'2*int((nf+1)/2) * (W/nf + 0.29)'"
as="'int((nf+2)/2) * W/nf * 0.29'" 
ps="'2*int((nf+2)/2) * (W/nf + 0.29)'"
nrd="'0.29 / W'" nrs="'0.29 / W'"
sa=0 sb=0 sd=0
model=nfet_g5v0d10v5
spiceprefix=X
}
C {devices/lab_pin.sym} 1845 -335 0 0 {name=l20 lab=N1


}
C {devices/lab_pin.sym} 2055 -245 0 0 {name=p41 sig_type=std_logic lab=avss


}
C {devices/lab_pin.sym} 1845 -245 0 1 {name=p44 sig_type=std_logic lab=avss


}
C {devices/isource.sym} 1955 -100 0 0 {name=I4 value=1n}
C {devices/lab_pin.sym} 1955 -70 0 0 {name=p45 lab=avss
}
C {devices/lab_pin.sym} 1805 -245 2 1 {name=l9 lab=vout
}
C {devices/lab_pin.sym} 2970 -660 2 1 {name=l30 lab=SumOutBar
}
C {devices/lab_pin.sym} 2095 -245 0 1 {name=l31 lab=SumOutBar
}
C {devices/lab_pin.sym} 2055 -335 0 0 {name=l32 lab=N2

}
C {sky130_fd_pr/pfet_g5v0d10v5.sym} 2585 -175 0 1 {name=M27
L=2
W=6
nf=1
mult=1
ad="'int((nf+1)/2) * W/nf * 0.29'" 
pd="'2*int((nf+1)/2) * (W/nf + 0.29)'"
as="'int((nf+2)/2) * W/nf * 0.29'" 
ps="'2*int((nf+2)/2) * (W/nf + 0.29)'"
nrd="'0.29 / W'" nrs="'0.29 / W'"
sa=0 sb=0 sd=0
model=pfet_g5v0d10v5
spiceprefix=X
}
C {sky130_fd_pr/pfet_g5v0d10v5.sym} 2335 -175 0 0 {name=M28
L=2
W=6
nf=1
mult=1
ad="'int((nf+1)/2) * W/nf * 0.29'" 
pd="'2*int((nf+1)/2) * (W/nf + 0.29)'"
as="'int((nf+2)/2) * W/nf * 0.29'" 
ps="'2*int((nf+2)/2) * (W/nf + 0.29)'"
nrd="'0.29 / W'" nrs="'0.29 / W'"
sa=0 sb=0 sd=0
model=pfet_g5v0d10v5
spiceprefix=X
}
C {devices/lab_pin.sym} 2565 -175 0 0 {name=l33 lab=avdd
}
C {devices/lab_pin.sym} 2355 -175 0 1 {name=l36 lab=avdd
}
C {devices/isource.sym} 2450 -295 0 0 {name=I5 value=1n}
C {devices/lab_pin.sym} 2450 -325 0 0 {name=p47 lab=avdd

}
C {devices/lab_pin.sym} 2355 -125 0 0 {name=l37 lab=P1


}
C {devices/lab_pin.sym} 2565 -125 0 0 {name=l46 lab=P2


}
C {devices/lab_pin.sym} 2625 -175 0 1 {name=l47 lab=SumOutBar
}
C {devices/lab_pin.sym} 2315 -175 2 1 {name=l48 lab=vout
}
